VERSION 5.7 ;
BUSBITCHARS "[]" ;
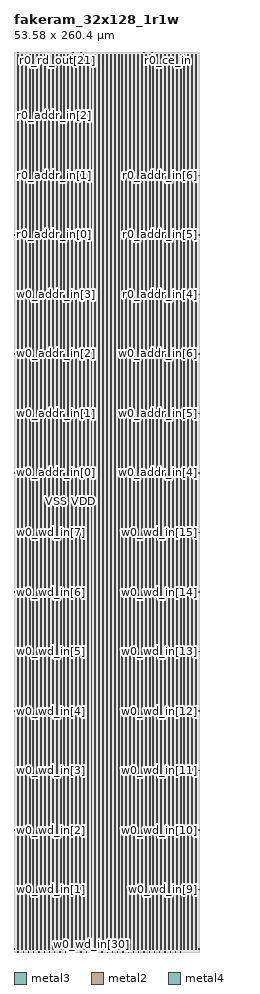
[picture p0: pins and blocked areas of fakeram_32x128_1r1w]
MACRO fakeram_32x128_1r1w
  FOREIGN fakeram_32x128_1r1w 0 0 ;
  SYMMETRY X Y R90 ;
  SIZE 53.580 BY 260.400 ;
  CLASS BLOCK ;
  PIN w0_wd_in[0]
    DIRECTION INPUT ;
    USE SIGNAL ;
    SHAPE ABUTMENT ;
    PORT
      LAYER metal3 ;
      RECT 0.000 0.805 0.210 0.875 ;
    END
  END w0_wd_in[0]
  PIN w0_wd_in[1]
    DIRECTION INPUT ;
    USE SIGNAL ;
    SHAPE ABUTMENT ;
    PORT
      LAYER metal3 ;
      RECT 0.000 18.025 0.210 18.095 ;
    END
  END w0_wd_in[1]
  PIN w0_wd_in[2]
    DIRECTION INPUT ;
    USE SIGNAL ;
    SHAPE ABUTMENT ;
    PORT
      LAYER metal3 ;
      RECT 0.000 35.245 0.210 35.315 ;
    END
  END w0_wd_in[2]
  PIN w0_wd_in[3]
    DIRECTION INPUT ;
    USE SIGNAL ;
    SHAPE ABUTMENT ;
    PORT
      LAYER metal3 ;
      RECT 0.000 52.465 0.210 52.535 ;
    END
  END w0_wd_in[3]
  PIN w0_wd_in[4]
    DIRECTION INPUT ;
    USE SIGNAL ;
    SHAPE ABUTMENT ;
    PORT
      LAYER metal3 ;
      RECT 0.000 69.685 0.210 69.755 ;
    END
  END w0_wd_in[4]
  PIN w0_wd_in[5]
    DIRECTION INPUT ;
    USE SIGNAL ;
    SHAPE ABUTMENT ;
    PORT
      LAYER metal3 ;
      RECT 0.000 86.905 0.210 86.975 ;
    END
  END w0_wd_in[5]
  PIN w0_wd_in[6]
    DIRECTION INPUT ;
    USE SIGNAL ;
    SHAPE ABUTMENT ;
    PORT
      LAYER metal3 ;
      RECT 0.000 104.125 0.210 104.195 ;
    END
  END w0_wd_in[6]
  PIN w0_wd_in[7]
    DIRECTION INPUT ;
    USE SIGNAL ;
    SHAPE ABUTMENT ;
    PORT
      LAYER metal3 ;
      RECT 0.000 121.345 0.210 121.415 ;
    END
  END w0_wd_in[7]
  PIN w0_wd_in[8]
    DIRECTION INPUT ;
    USE SIGNAL ;
    SHAPE ABUTMENT ;
    PORT
      LAYER metal3 ;
      RECT 53.370 0.805 53.580 0.875 ;
    END
  END w0_wd_in[8]
  PIN w0_wd_in[9]
    DIRECTION INPUT ;
    USE SIGNAL ;
    SHAPE ABUTMENT ;
    PORT
      LAYER metal3 ;
      RECT 53.370 18.025 53.580 18.095 ;
    END
  END w0_wd_in[9]
  PIN w0_wd_in[10]
    DIRECTION INPUT ;
    USE SIGNAL ;
    SHAPE ABUTMENT ;
    PORT
      LAYER metal3 ;
      RECT 53.370 35.245 53.580 35.315 ;
    END
  END w0_wd_in[10]
  PIN w0_wd_in[11]
    DIRECTION INPUT ;
    USE SIGNAL ;
    SHAPE ABUTMENT ;
    PORT
      LAYER metal3 ;
      RECT 53.370 52.465 53.580 52.535 ;
    END
  END w0_wd_in[11]
  PIN w0_wd_in[12]
    DIRECTION INPUT ;
    USE SIGNAL ;
    SHAPE ABUTMENT ;
    PORT
      LAYER metal3 ;
      RECT 53.370 69.685 53.580 69.755 ;
    END
  END w0_wd_in[12]
  PIN w0_wd_in[13]
    DIRECTION INPUT ;
    USE SIGNAL ;
    SHAPE ABUTMENT ;
    PORT
      LAYER metal3 ;
      RECT 53.370 86.905 53.580 86.975 ;
    END
  END w0_wd_in[13]
  PIN w0_wd_in[14]
    DIRECTION INPUT ;
    USE SIGNAL ;
    SHAPE ABUTMENT ;
    PORT
      LAYER metal3 ;
      RECT 53.370 104.125 53.580 104.195 ;
    END
  END w0_wd_in[14]
  PIN w0_wd_in[15]
    DIRECTION INPUT ;
    USE SIGNAL ;
    SHAPE ABUTMENT ;
    PORT
      LAYER metal3 ;
      RECT 53.370 121.345 53.580 121.415 ;
    END
  END w0_wd_in[15]
  PIN w0_wd_in[16]
    DIRECTION INPUT ;
    USE SIGNAL ;
    SHAPE ABUTMENT ;
    PORT
      LAYER metal2 ;
      RECT 1.105 0.000 1.175 0.210 ;
    END
  END w0_wd_in[16]
  PIN w0_wd_in[17]
    DIRECTION INPUT ;
    USE SIGNAL ;
    SHAPE ABUTMENT ;
    PORT
      LAYER metal2 ;
      RECT 2.625 0.000 2.695 0.210 ;
    END
  END w0_wd_in[17]
  PIN w0_wd_in[18]
    DIRECTION INPUT ;
    USE SIGNAL ;
    SHAPE ABUTMENT ;
    PORT
      LAYER metal2 ;
      RECT 4.145 0.000 4.215 0.210 ;
    END
  END w0_wd_in[18]
  PIN w0_wd_in[19]
    DIRECTION INPUT ;
    USE SIGNAL ;
    SHAPE ABUTMENT ;
    PORT
      LAYER metal2 ;
      RECT 5.665 0.000 5.735 0.210 ;
    END
  END w0_wd_in[19]
  PIN w0_wd_in[20]
    DIRECTION INPUT ;
    USE SIGNAL ;
    SHAPE ABUTMENT ;
    PORT
      LAYER metal2 ;
      RECT 7.185 0.000 7.255 0.210 ;
    END
  END w0_wd_in[20]
  PIN w0_wd_in[21]
    DIRECTION INPUT ;
    USE SIGNAL ;
    SHAPE ABUTMENT ;
    PORT
      LAYER metal2 ;
      RECT 8.705 0.000 8.775 0.210 ;
    END
  END w0_wd_in[21]
  PIN w0_wd_in[22]
    DIRECTION INPUT ;
    USE SIGNAL ;
    SHAPE ABUTMENT ;
    PORT
      LAYER metal2 ;
      RECT 10.225 0.000 10.295 0.210 ;
    END
  END w0_wd_in[22]
  PIN w0_wd_in[23]
    DIRECTION INPUT ;
    USE SIGNAL ;
    SHAPE ABUTMENT ;
    PORT
      LAYER metal2 ;
      RECT 11.745 0.000 11.815 0.210 ;
    END
  END w0_wd_in[23]
  PIN w0_wd_in[24]
    DIRECTION INPUT ;
    USE SIGNAL ;
    SHAPE ABUTMENT ;
    PORT
      LAYER metal2 ;
      RECT 13.265 0.000 13.335 0.210 ;
    END
  END w0_wd_in[24]
  PIN w0_wd_in[25]
    DIRECTION INPUT ;
    USE SIGNAL ;
    SHAPE ABUTMENT ;
    PORT
      LAYER metal2 ;
      RECT 14.785 0.000 14.855 0.210 ;
    END
  END w0_wd_in[25]
  PIN w0_wd_in[26]
    DIRECTION INPUT ;
    USE SIGNAL ;
    SHAPE ABUTMENT ;
    PORT
      LAYER metal2 ;
      RECT 16.305 0.000 16.375 0.210 ;
    END
  END w0_wd_in[26]
  PIN w0_wd_in[27]
    DIRECTION INPUT ;
    USE SIGNAL ;
    SHAPE ABUTMENT ;
    PORT
      LAYER metal2 ;
      RECT 17.825 0.000 17.895 0.210 ;
    END
  END w0_wd_in[27]
  PIN w0_wd_in[28]
    DIRECTION INPUT ;
    USE SIGNAL ;
    SHAPE ABUTMENT ;
    PORT
      LAYER metal2 ;
      RECT 19.345 0.000 19.415 0.210 ;
    END
  END w0_wd_in[28]
  PIN w0_wd_in[29]
    DIRECTION INPUT ;
    USE SIGNAL ;
    SHAPE ABUTMENT ;
    PORT
      LAYER metal2 ;
      RECT 20.865 0.000 20.935 0.210 ;
    END
  END w0_wd_in[29]
  PIN w0_wd_in[30]
    DIRECTION INPUT ;
    USE SIGNAL ;
    SHAPE ABUTMENT ;
    PORT
      LAYER metal2 ;
      RECT 22.385 0.000 22.455 0.210 ;
    END
  END w0_wd_in[30]
  PIN w0_wd_in[31]
    DIRECTION INPUT ;
    USE SIGNAL ;
    SHAPE ABUTMENT ;
    PORT
      LAYER metal2 ;
      RECT 23.905 0.000 23.975 0.210 ;
    END
  END w0_wd_in[31]
  PIN r0_rd_out[0]
    DIRECTION OUTPUT ;
    USE SIGNAL ;
    SHAPE ABUTMENT ;
    PORT
      LAYER metal2 ;
      RECT 25.425 0.000 25.495 0.210 ;
    END
  END r0_rd_out[0]
  PIN r0_rd_out[1]
    DIRECTION OUTPUT ;
    USE SIGNAL ;
    SHAPE ABUTMENT ;
    PORT
      LAYER metal2 ;
      RECT 26.945 0.000 27.015 0.210 ;
    END
  END r0_rd_out[1]
  PIN r0_rd_out[2]
    DIRECTION OUTPUT ;
    USE SIGNAL ;
    SHAPE ABUTMENT ;
    PORT
      LAYER metal2 ;
      RECT 28.465 0.000 28.535 0.210 ;
    END
  END r0_rd_out[2]
  PIN r0_rd_out[3]
    DIRECTION OUTPUT ;
    USE SIGNAL ;
    SHAPE ABUTMENT ;
    PORT
      LAYER metal2 ;
      RECT 29.985 0.000 30.055 0.210 ;
    END
  END r0_rd_out[3]
  PIN r0_rd_out[4]
    DIRECTION OUTPUT ;
    USE SIGNAL ;
    SHAPE ABUTMENT ;
    PORT
      LAYER metal2 ;
      RECT 31.505 0.000 31.575 0.210 ;
    END
  END r0_rd_out[4]
  PIN r0_rd_out[5]
    DIRECTION OUTPUT ;
    USE SIGNAL ;
    SHAPE ABUTMENT ;
    PORT
      LAYER metal2 ;
      RECT 33.025 0.000 33.095 0.210 ;
    END
  END r0_rd_out[5]
  PIN r0_rd_out[6]
    DIRECTION OUTPUT ;
    USE SIGNAL ;
    SHAPE ABUTMENT ;
    PORT
      LAYER metal2 ;
      RECT 34.545 0.000 34.615 0.210 ;
    END
  END r0_rd_out[6]
  PIN r0_rd_out[7]
    DIRECTION OUTPUT ;
    USE SIGNAL ;
    SHAPE ABUTMENT ;
    PORT
      LAYER metal2 ;
      RECT 36.065 0.000 36.135 0.210 ;
    END
  END r0_rd_out[7]
  PIN r0_rd_out[8]
    DIRECTION OUTPUT ;
    USE SIGNAL ;
    SHAPE ABUTMENT ;
    PORT
      LAYER metal2 ;
      RECT 37.585 0.000 37.655 0.210 ;
    END
  END r0_rd_out[8]
  PIN r0_rd_out[9]
    DIRECTION OUTPUT ;
    USE SIGNAL ;
    SHAPE ABUTMENT ;
    PORT
      LAYER metal2 ;
      RECT 39.105 0.000 39.175 0.210 ;
    END
  END r0_rd_out[9]
  PIN r0_rd_out[10]
    DIRECTION OUTPUT ;
    USE SIGNAL ;
    SHAPE ABUTMENT ;
    PORT
      LAYER metal2 ;
      RECT 40.625 0.000 40.695 0.210 ;
    END
  END r0_rd_out[10]
  PIN r0_rd_out[11]
    DIRECTION OUTPUT ;
    USE SIGNAL ;
    SHAPE ABUTMENT ;
    PORT
      LAYER metal2 ;
      RECT 42.145 0.000 42.215 0.210 ;
    END
  END r0_rd_out[11]
  PIN r0_rd_out[12]
    DIRECTION OUTPUT ;
    USE SIGNAL ;
    SHAPE ABUTMENT ;
    PORT
      LAYER metal2 ;
      RECT 43.665 0.000 43.735 0.210 ;
    END
  END r0_rd_out[12]
  PIN r0_rd_out[13]
    DIRECTION OUTPUT ;
    USE SIGNAL ;
    SHAPE ABUTMENT ;
    PORT
      LAYER metal2 ;
      RECT 45.185 0.000 45.255 0.210 ;
    END
  END r0_rd_out[13]
  PIN r0_rd_out[14]
    DIRECTION OUTPUT ;
    USE SIGNAL ;
    SHAPE ABUTMENT ;
    PORT
      LAYER metal2 ;
      RECT 46.705 0.000 46.775 0.210 ;
    END
  END r0_rd_out[14]
  PIN r0_rd_out[15]
    DIRECTION OUTPUT ;
    USE SIGNAL ;
    SHAPE ABUTMENT ;
    PORT
      LAYER metal2 ;
      RECT 48.225 0.000 48.295 0.210 ;
    END
  END r0_rd_out[15]
  PIN r0_rd_out[16]
    DIRECTION OUTPUT ;
    USE SIGNAL ;
    SHAPE ABUTMENT ;
    PORT
      LAYER metal2 ;
      RECT 1.105 260.190 1.175 260.400 ;
    END
  END r0_rd_out[16]
  PIN r0_rd_out[17]
    DIRECTION OUTPUT ;
    USE SIGNAL ;
    SHAPE ABUTMENT ;
    PORT
      LAYER metal2 ;
      RECT 3.385 260.190 3.455 260.400 ;
    END
  END r0_rd_out[17]
  PIN r0_rd_out[18]
    DIRECTION OUTPUT ;
    USE SIGNAL ;
    SHAPE ABUTMENT ;
    PORT
      LAYER metal2 ;
      RECT 5.665 260.190 5.735 260.400 ;
    END
  END r0_rd_out[18]
  PIN r0_rd_out[19]
    DIRECTION OUTPUT ;
    USE SIGNAL ;
    SHAPE ABUTMENT ;
    PORT
      LAYER metal2 ;
      RECT 7.945 260.190 8.015 260.400 ;
    END
  END r0_rd_out[19]
  PIN r0_rd_out[20]
    DIRECTION OUTPUT ;
    USE SIGNAL ;
    SHAPE ABUTMENT ;
    PORT
      LAYER metal2 ;
      RECT 10.225 260.190 10.295 260.400 ;
    END
  END r0_rd_out[20]
  PIN r0_rd_out[21]
    DIRECTION OUTPUT ;
    USE SIGNAL ;
    SHAPE ABUTMENT ;
    PORT
      LAYER metal2 ;
      RECT 12.505 260.190 12.575 260.400 ;
    END
  END r0_rd_out[21]
  PIN r0_rd_out[22]
    DIRECTION OUTPUT ;
    USE SIGNAL ;
    SHAPE ABUTMENT ;
    PORT
      LAYER metal2 ;
      RECT 14.785 260.190 14.855 260.400 ;
    END
  END r0_rd_out[22]
  PIN r0_rd_out[23]
    DIRECTION OUTPUT ;
    USE SIGNAL ;
    SHAPE ABUTMENT ;
    PORT
      LAYER metal2 ;
      RECT 17.065 260.190 17.135 260.400 ;
    END
  END r0_rd_out[23]
  PIN r0_rd_out[24]
    DIRECTION OUTPUT ;
    USE SIGNAL ;
    SHAPE ABUTMENT ;
    PORT
      LAYER metal2 ;
      RECT 19.345 260.190 19.415 260.400 ;
    END
  END r0_rd_out[24]
  PIN r0_rd_out[25]
    DIRECTION OUTPUT ;
    USE SIGNAL ;
    SHAPE ABUTMENT ;
    PORT
      LAYER metal2 ;
      RECT 21.625 260.190 21.695 260.400 ;
    END
  END r0_rd_out[25]
  PIN r0_rd_out[26]
    DIRECTION OUTPUT ;
    USE SIGNAL ;
    SHAPE ABUTMENT ;
    PORT
      LAYER metal2 ;
      RECT 23.905 260.190 23.975 260.400 ;
    END
  END r0_rd_out[26]
  PIN r0_rd_out[27]
    DIRECTION OUTPUT ;
    USE SIGNAL ;
    SHAPE ABUTMENT ;
    PORT
      LAYER metal2 ;
      RECT 26.185 260.190 26.255 260.400 ;
    END
  END r0_rd_out[27]
  PIN r0_rd_out[28]
    DIRECTION OUTPUT ;
    USE SIGNAL ;
    SHAPE ABUTMENT ;
    PORT
      LAYER metal2 ;
      RECT 28.465 260.190 28.535 260.400 ;
    END
  END r0_rd_out[28]
  PIN r0_rd_out[29]
    DIRECTION OUTPUT ;
    USE SIGNAL ;
    SHAPE ABUTMENT ;
    PORT
      LAYER metal2 ;
      RECT 30.745 260.190 30.815 260.400 ;
    END
  END r0_rd_out[29]
  PIN r0_rd_out[30]
    DIRECTION OUTPUT ;
    USE SIGNAL ;
    SHAPE ABUTMENT ;
    PORT
      LAYER metal2 ;
      RECT 33.025 260.190 33.095 260.400 ;
    END
  END r0_rd_out[30]
  PIN r0_rd_out[31]
    DIRECTION OUTPUT ;
    USE SIGNAL ;
    SHAPE ABUTMENT ;
    PORT
      LAYER metal2 ;
      RECT 35.305 260.190 35.375 260.400 ;
    END
  END r0_rd_out[31]
  PIN w0_addr_in[0]
    DIRECTION INPUT ;
    USE SIGNAL ;
    SHAPE ABUTMENT ;
    PORT
      LAYER metal3 ;
      RECT 0.000 138.565 0.210 138.635 ;
    END
  END w0_addr_in[0]
  PIN w0_addr_in[1]
    DIRECTION INPUT ;
    USE SIGNAL ;
    SHAPE ABUTMENT ;
    PORT
      LAYER metal3 ;
      RECT 0.000 155.785 0.210 155.855 ;
    END
  END w0_addr_in[1]
  PIN w0_addr_in[2]
    DIRECTION INPUT ;
    USE SIGNAL ;
    SHAPE ABUTMENT ;
    PORT
      LAYER metal3 ;
      RECT 0.000 173.005 0.210 173.075 ;
    END
  END w0_addr_in[2]
  PIN w0_addr_in[3]
    DIRECTION INPUT ;
    USE SIGNAL ;
    SHAPE ABUTMENT ;
    PORT
      LAYER metal3 ;
      RECT 0.000 190.225 0.210 190.295 ;
    END
  END w0_addr_in[3]
  PIN w0_addr_in[4]
    DIRECTION INPUT ;
    USE SIGNAL ;
    SHAPE ABUTMENT ;
    PORT
      LAYER metal3 ;
      RECT 53.370 138.565 53.580 138.635 ;
    END
  END w0_addr_in[4]
  PIN w0_addr_in[5]
    DIRECTION INPUT ;
    USE SIGNAL ;
    SHAPE ABUTMENT ;
    PORT
      LAYER metal3 ;
      RECT 53.370 155.785 53.580 155.855 ;
    END
  END w0_addr_in[5]
  PIN w0_addr_in[6]
    DIRECTION INPUT ;
    USE SIGNAL ;
    SHAPE ABUTMENT ;
    PORT
      LAYER metal3 ;
      RECT 53.370 173.005 53.580 173.075 ;
    END
  END w0_addr_in[6]
  PIN r0_addr_in[0]
    DIRECTION INPUT ;
    USE SIGNAL ;
    SHAPE ABUTMENT ;
    PORT
      LAYER metal3 ;
      RECT 0.000 207.445 0.210 207.515 ;
    END
  END r0_addr_in[0]
  PIN r0_addr_in[1]
    DIRECTION INPUT ;
    USE SIGNAL ;
    SHAPE ABUTMENT ;
    PORT
      LAYER metal3 ;
      RECT 0.000 224.665 0.210 224.735 ;
    END
  END r0_addr_in[1]
  PIN r0_addr_in[2]
    DIRECTION INPUT ;
    USE SIGNAL ;
    SHAPE ABUTMENT ;
    PORT
      LAYER metal3 ;
      RECT 0.000 241.885 0.210 241.955 ;
    END
  END r0_addr_in[2]
  PIN r0_addr_in[3]
    DIRECTION INPUT ;
    USE SIGNAL ;
    SHAPE ABUTMENT ;
    PORT
      LAYER metal3 ;
      RECT 0.000 259.105 0.210 259.175 ;
    END
  END r0_addr_in[3]
  PIN r0_addr_in[4]
    DIRECTION INPUT ;
    USE SIGNAL ;
    SHAPE ABUTMENT ;
    PORT
      LAYER metal3 ;
      RECT 53.370 190.225 53.580 190.295 ;
    END
  END r0_addr_in[4]
  PIN r0_addr_in[5]
    DIRECTION INPUT ;
    USE SIGNAL ;
    SHAPE ABUTMENT ;
    PORT
      LAYER metal3 ;
      RECT 53.370 207.445 53.580 207.515 ;
    END
  END r0_addr_in[5]
  PIN r0_addr_in[6]
    DIRECTION INPUT ;
    USE SIGNAL ;
    SHAPE ABUTMENT ;
    PORT
      LAYER metal3 ;
      RECT 53.370 224.665 53.580 224.735 ;
    END
  END r0_addr_in[6]
  PIN w0_we_in
    DIRECTION INPUT ;
    USE SIGNAL ;
    SHAPE ABUTMENT ;
    PORT
      LAYER metal2 ;
      RECT 37.585 260.190 37.655 260.400 ;
    END
  END w0_we_in
  PIN w0_ce_in
    DIRECTION INPUT ;
    USE SIGNAL ;
    SHAPE ABUTMENT ;
    PORT
      LAYER metal2 ;
      RECT 39.865 260.190 39.935 260.400 ;
    END
  END w0_ce_in
  PIN w0_clk
    DIRECTION INPUT ;
    USE SIGNAL ;
    SHAPE ABUTMENT ;
    PORT
      LAYER metal2 ;
      RECT 42.145 260.190 42.215 260.400 ;
    END
  END w0_clk
  PIN r0_ce_in
    DIRECTION INPUT ;
    USE SIGNAL ;
    SHAPE ABUTMENT ;
    PORT
      LAYER metal2 ;
      RECT 44.425 260.190 44.495 260.400 ;
    END
  END r0_ce_in
  PIN r0_clk
    DIRECTION INPUT ;
    USE SIGNAL ;
    SHAPE ABUTMENT ;
    PORT
      LAYER metal2 ;
      RECT 46.705 260.190 46.775 260.400 ;
    END
  END r0_clk
  PIN VSS
    DIRECTION INOUT ;
    USE GROUND ;
    PORT
      LAYER metal4 ;
      RECT 1.000 0.840 1.280 259.560 ;
      RECT 3.240 0.840 3.520 259.560 ;
      RECT 5.480 0.840 5.760 259.560 ;
      RECT 7.720 0.840 8.000 259.560 ;
      RECT 9.960 0.840 10.240 259.560 ;
      RECT 12.200 0.840 12.480 259.560 ;
      RECT 14.440 0.840 14.720 259.560 ;
      RECT 16.680 0.840 16.960 259.560 ;
      RECT 18.920 0.840 19.200 259.560 ;
      RECT 21.160 0.840 21.440 259.560 ;
      RECT 23.400 0.840 23.680 259.560 ;
      RECT 25.640 0.840 25.920 259.560 ;
      RECT 27.880 0.840 28.160 259.560 ;
      RECT 30.120 0.840 30.400 259.560 ;
      RECT 32.360 0.840 32.640 259.560 ;
      RECT 34.600 0.840 34.880 259.560 ;
      RECT 36.840 0.840 37.120 259.560 ;
      RECT 39.080 0.840 39.360 259.560 ;
      RECT 41.320 0.840 41.600 259.560 ;
      RECT 43.560 0.840 43.840 259.560 ;
      RECT 45.800 0.840 46.080 259.560 ;
      RECT 48.040 0.840 48.320 259.560 ;
      RECT 50.280 0.840 50.560 259.560 ;
      RECT 52.520 0.840 52.800 259.560 ;
    END
  END VSS
  PIN VDD
    DIRECTION INOUT ;
    USE POWER ;
    PORT
      LAYER metal4 ;
      RECT 2.120 0.840 2.400 259.560 ;
      RECT 4.360 0.840 4.640 259.560 ;
      RECT 6.600 0.840 6.880 259.560 ;
      RECT 8.840 0.840 9.120 259.560 ;
      RECT 11.080 0.840 11.360 259.560 ;
      RECT 13.320 0.840 13.600 259.560 ;
      RECT 15.560 0.840 15.840 259.560 ;
      RECT 17.800 0.840 18.080 259.560 ;
      RECT 20.040 0.840 20.320 259.560 ;
      RECT 22.280 0.840 22.560 259.560 ;
      RECT 24.520 0.840 24.800 259.560 ;
      RECT 26.760 0.840 27.040 259.560 ;
      RECT 29.000 0.840 29.280 259.560 ;
      RECT 31.240 0.840 31.520 259.560 ;
      RECT 33.480 0.840 33.760 259.560 ;
      RECT 35.720 0.840 36.000 259.560 ;
      RECT 37.960 0.840 38.240 259.560 ;
      RECT 40.200 0.840 40.480 259.560 ;
      RECT 42.440 0.840 42.720 259.560 ;
      RECT 44.680 0.840 44.960 259.560 ;
      RECT 46.920 0.840 47.200 259.560 ;
      RECT 49.160 0.840 49.440 259.560 ;
      RECT 51.400 0.840 51.680 259.560 ;
    END
  END VDD
  OBS
    LAYER metal1 ;
    RECT 0 0 53.580 260.400 ;
    LAYER metal2 ;
    RECT 0 0 53.580 260.400 ;
    LAYER metal3 ;
    RECT 0 0 53.580 260.400 ;
    LAYER metal4 ;
    RECT 0 0 53.580 260.400 ;
    LAYER OVERLAP ;
    RECT 0 0 53.580 260.400 ;
  END
END fakeram_32x128_1r1w

END LIBRARY
